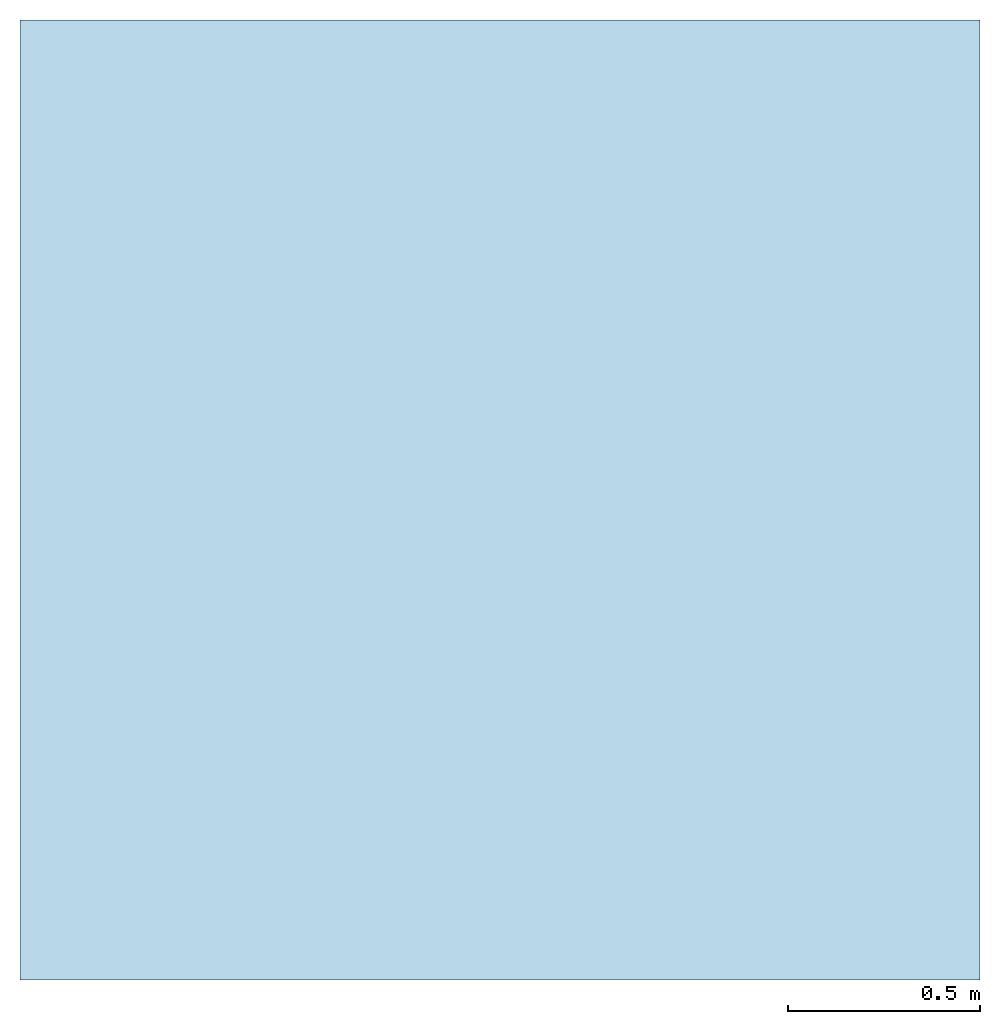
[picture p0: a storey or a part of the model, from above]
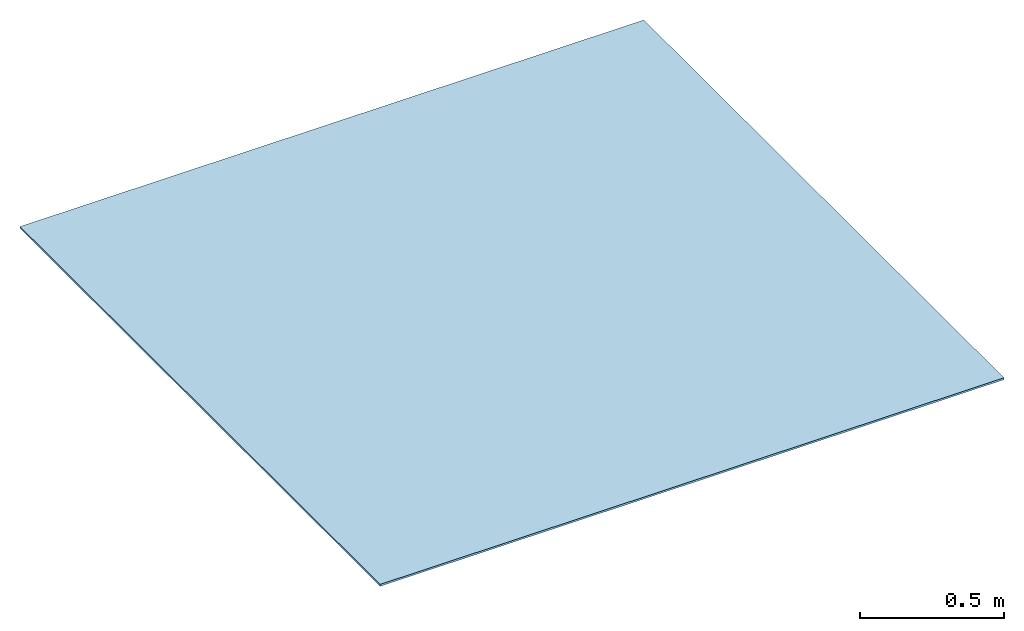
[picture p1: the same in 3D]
Properties of the parts of a building model (IFC2X3)

# File
Description: ViewDefinition[CoordinationView]
Time: 2017-03-02T10:26:18
Author: NBS
Written by: Xbim.Ifc File Processor version 2.4.1.0
Made in: Xbim version 2.4.1.0
Authorization: Add company name here

# IfcSlab: NBS_DeltaMembranes_VapourPermeableSheets_DeltaTrelaPlus
In: Default building
Type - PredefinedType: ROOF; Material: NBS_DeltaMembranes_VapourPermeableSheets_DeltaTrelaPlus 8 mm
Type - xbim_MaterialFunctionAssignment - MaterialFunctionAssignment: 0: Substrate
Type - COBie - AccessibilityPerformance: n/a; AssetType: n/a; Category: Pr_25_57_10_94:Vapour permeable sheets; CodePerformance: n/a; Color: n/a; Constituents: n/a; Description: Delta®-Trela Plus consist of a 3-ply spun-bonded polypropylene breather underlay sheet laminated to a dimple-textured random-fibre spacer mat to provide a permanent air gap under the cladding, preventing moisture, with an self-adhesive edge.; DurationUnit: n/a; ExpectedLife: n/a; Features: n/a; Grade: n/a; Manufacturer: info@deltamembranes.com; ModelNumber: n/a; ModelReference: Delta-Trela Plus; Name: VapourPermeableSheets_DeltaTrelaPlus_DeltaMembranes; NominalHeight: 8 mm; NominalLength: 0 mm; NominalWidth: 0 mm; ReplacementCost: n/a; Shape: n/a; Size: n/a; SustainabilityPerformance: n/a; WarrantyDescription: n/a; WarrantyDurationLabor: n/a; WarrantyDurationParts: n/a; WarrantyDurationUnit: year; WarrantyGuarantorLabor: n/a; WarrantyGuarantorParts: n/a
Type - Pset_CoveringCommon - AcousticRating: n/a; Combustible: no; Finish: n/a; FireRating: B2 rating to DIN 4102; FlammabilityRating: Class E, BS EN 13501-1; FragilityRating: n/a; Material: n/a; Reference: n/a; SurfaceSpreadOfFlame: n/a; TotalThickness: 8
Type - NBS_Data - AntistaticProperties: n/a; BackingSheet: DELTA®-VENT S, a 3-layer highly breathable underlay of PP cloth; Certification: n/a; DimpledMat: Polypropylene polyamide (DELTA®-TRELA ST); DimpleHeight: 8 mm; Form: n/a; RollSize: 30 x 1.5 m; RollWeight: 17.1 kg; RollWidth: 1500 mm; UVStabilization: n/a; WeightMinimum: 380 g/m²
Type - NBS_General - Author: NBS; BIMObjectName: NBS_DeltaMembranes_VapourPermeableSheets_DeltaTrelaPlus; ManufacturerName: Delta Membrane Systems Ltd; ManufacturerURL: www.deltamembranes.com/; NBSCertification: www.nationalbimlibrary.com/cert/osgrzhxh; NBSDescription: Vapour permeable sheets; NBSNote: n/a; NBSOfficeMasterTag: n/a; NBSReference: 45-65-50/323; NBSTypeID: n/a; ProductInformation: www.deltamembranes.com/pdf/Delta-Trela-New.pdf; Revision: n/a; Uniclass2015Code: Pr_25_57_10_94; Uniclass2015Title: Vapour permeable sheets; Uniclass2015Version: Products v1.4; Version: 5
COBie - AssetIdentifier: n/a; BarCode: n/a; InstallationDate: 1900-12-31T23:59:59; SerialNumber: n/a; TagNumber: n/a; WarrantyStartDate: 1900-12-31T23:59:59
